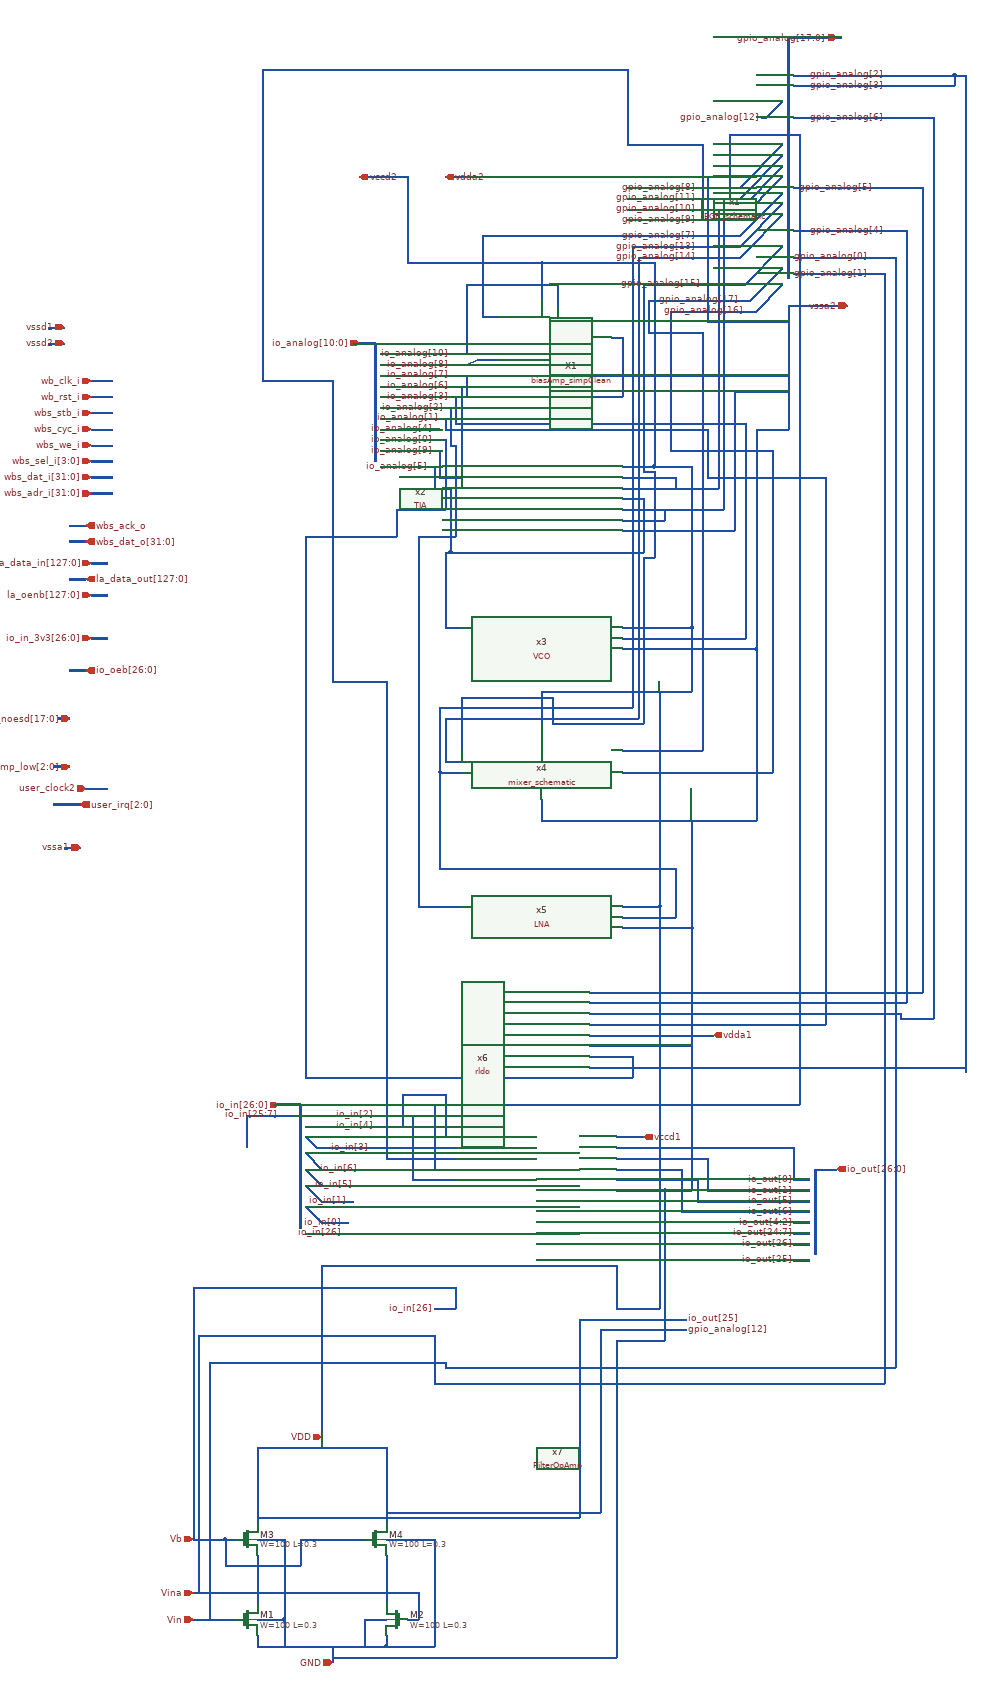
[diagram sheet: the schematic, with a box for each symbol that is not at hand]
v {xschem version=3.0.0 file_version=1.2 }
G {}
K {}
V {}
S {}
E {}
N 5340 -670 5340 -550 { lab=gpio_analog[17:0]
bus=true}
N 5340 -550 5340 -530 { lab=gpio_analog[17:0]
bus=true}
N 5040 -550 5250 -550 { lab=gpio_analog[8]}
N 5250 -550 5330 -630 { lab=gpio_analog[8]}
N 5040 -530 5250 -530 { lab=gpio_analog[11]}
N 5250 -530 5330 -610 { lab=gpio_analog[11]}
N 5040 -510 5250 -510 { lab=gpio_analog[10]}
N 5250 -510 5330 -590 { lab=gpio_analog[10]}
N 5040 -490 5250 -490 { lab=gpio_analog[9]}
N 5250 -490 5330 -570 { lab=gpio_analog[9]}
N 5340 -330 5450 -330 { lab=vssa2}
N 5340 -330 5340 -100 { lab=vssa2}
N 5040 -570 5190 -570 { lab=vssa2}
N 5190 -570 5190 -300 { lab=vssa2}
N 5190 -300 5330 -300 { lab=vssa2}
N 5330 -300 5340 -300 { lab=vssa2}
N 4880 -410 4880 -340 { lab=vccd2}
N 4630 -410 4880 -410 { lab=vccd2}
N 4630 -570 4630 -410 { lab=vccd2}
N 4880 -200 5340 -200 { lab=vssa2}
N 4530 -260 4570 -260 { lab=io_analog[10:0]
bus=true}
N 4580 -240 4670 -240 { lab=io_analog[10]}
N 4670 -240 4740 -240 { lab=io_analog[10]}
N 4740 -370 4740 -240 { lab=io_analog[10]}
N 4740 -370 4910 -370 { lab=io_analog[10]}
N 4580 -220 4740 -220 { lab=io_analog[8]}
N 4740 -220 4760 -230 { lab=io_analog[8]}
N 4760 -230 4800 -230 { lab=io_analog[8]}
N 4770 -310 4800 -310 { lab=gpio_analog[7]}
N 4770 -430 4770 -310 { lab=gpio_analog[7]}
N 4770 -460 4770 -430 { lab=gpio_analog[7]}
N 4770 -460 5250 -460 { lab=gpio_analog[7]}
N 5250 -460 5330 -540 { lab=gpio_analog[7]}
N 4580 -200 4740 -200 { lab=io_analog[7]}
N 4740 -200 4740 -160 { lab=io_analog[7]}
N 4740 -160 5030 -160 { lab=io_analog[7]}
N 5030 -270 5030 -160 { lab=io_analog[7]}
N 5010 -270 5030 -270 { lab=io_analog[7]}
N 5030 -30 5090 -30 { lab=vccd2}
N 5090 -410 5090 -30 { lab=vccd2}
N 4880 -410 5090 -410 { lab=vccd2}
N 5030 90 5240 90 { lab=vssa2}
N 5240 -170 5240 90 { lab=vssa2}
N 5240 -170 5340 -170 { lab=vssa2}
N 5030 10 5210 10 { lab=gpio_analog[10]}
N 5210 -510 5210 10 { lab=gpio_analog[10]}
N 5030 -10 5130 -10 { lab=gpio_analog[10]}
N 5130 -10 5130 10 { lab=gpio_analog[10]}
N 5030 50 5220 50 { lab=gpio_analog[11]}
N 5220 -530 5220 50 { lab=gpio_analog[11]}
N 4580 -180 4730 -180 { lab=io_analog[6]}
N 4730 -180 4730 -30 { lab=io_analog[6]}
N 5030 70 5110 70 { lab=gpio_analog[11]}
N 5110 50 5110 70 { lab=gpio_analog[11]}
N 4710 10 4710 130 { lab=io_analog[5]}
N 4710 130 5070 130 { lab=io_analog[5]}
N 5070 30 5070 130 { lab=io_analog[5]}
N 5030 30 5070 30 { lab=io_analog[5]}
N 4700 270 4730 270 { lab=io_analog[5]}
N 4700 130 4700 270 { lab=io_analog[5]}
N 4700 130 4710 130 { lab=io_analog[5]}
N 5030 310 5280 310 { lab=vssa2}
N 5280 -100 5280 310 { lab=vssa2}
N 5280 -100 5340 -100 { lab=vssa2}
N 5030 270 5080 270 { lab=vccd2}
N 5160 -30 5160 190 { lab=vccd2}
N 5090 -30 5160 -30 { lab=vccd2}
N 5080 270 5160 270 { lab=vccd2}
N 5160 190 5160 270 { lab=vccd2}
N 4580 -160 4720 -160 { lab=io_analog[3]}
N 4720 -160 4720 -110 { lab=io_analog[3]}
N 4720 -110 5260 -110 { lab=io_analog[3]}
N 5260 -110 5260 290 { lab=io_analog[3]}
N 5030 290 5260 290 { lab=io_analog[3]}
N 4880 390 4880 450 { lab=vccd2}
N 4880 390 5160 390 { lab=vccd2}
N 5160 270 5160 390 { lab=vccd2}
N 4880 590 4880 630 { lab=vssa2}
N 4880 630 5280 630 { lab=vssa2}
N 5280 310 5280 630 { lab=vssa2}
N 4690 420 4690 540 { lab=gpio_analog[13]}
N 4690 540 4730 540 { lab=gpio_analog[13]}
N 5250 -440 5330 -520 { lab=gpio_analog[13]}
N 5050 -440 5250 -440 { lab=gpio_analog[13]}
N 5050 -440 5050 420 { lab=gpio_analog[13]}
N 4690 420 5050 420 { lab=gpio_analog[13]}
N 5340 -530 5340 -450 { lab=gpio_analog[17:0]
bus=true}
N 5260 -430 5330 -500 { lab=gpio_analog[14]}
N 5250 -420 5260 -430 { lab=gpio_analog[14]}
N 5060 -420 5250 -420 { lab=gpio_analog[14]}
N 5060 -420 5060 440 { lab=gpio_analog[14]}
N 4700 440 5060 440 { lab=gpio_analog[14]}
N 4700 440 4700 520 { lab=gpio_analog[14]}
N 4700 520 4730 520 { lab=gpio_analog[14]}
N 5260 -370 5330 -440 { lab=gpio_analog[15]}
N 5070 -370 5260 -370 { lab=gpio_analog[15]}
N 4900 450 5070 450 { lab=gpio_analog[15]}
N 4900 400 4900 450 { lab=gpio_analog[15]}
N 4730 400 4900 400 { lab=gpio_analog[15]}
N 4730 400 4730 500 { lab=gpio_analog[15]}
N 5340 -450 5340 -410 { lab=gpio_analog[17:0]
bus=true}
N 5270 -340 5330 -400 { lab=gpio_analog[17]}
N 5080 -340 5270 -340 { lab=gpio_analog[17]}
N 5030 500 5080 500 { lab=gpio_analog[17]}
N 5080 -340 5080 -280 { lab=gpio_analog[17]}
N 5080 -280 5180 -280 { lab=gpio_analog[17]}
N 5180 -280 5180 500 { lab=gpio_analog[17]}
N 5080 500 5180 500 { lab=gpio_analog[17]}
N 5340 -410 5340 -380 { lab=gpio_analog[17:0]
bus=true}
N 5280 -320 5330 -370 { lab=gpio_analog[16]}
N 5120 -320 5280 -320 { lab=gpio_analog[16]}
N 5120 -320 5120 -60 { lab=gpio_analog[16]}
N 5120 -60 5310 -60 { lab=gpio_analog[16]}
N 5310 -60 5310 540 { lab=gpio_analog[16]}
N 5030 540 5310 540 { lab=gpio_analog[16]}
N 5030 790 5100 790 { lab=vccd2}
N 5100 390 5100 790 { lab=vccd2}
N 5030 830 5160 830 { lab=vssa2}
N 5160 630 5160 830 { lab=vssa2}
N 4650 790 4730 790 { lab=io_analog[2]}
N 4650 400 4650 790 { lab=io_analog[2]}
N 4690 540 4690 720 { lab=gpio_analog[13]}
N 4690 720 5130 720 { lab=gpio_analog[13]}
N 5130 720 5130 810 { lab=gpio_analog[13]}
N 5030 810 5130 810 { lab=gpio_analog[13]}
N 5020 1220 5070 1220 { lab=vccd1}
N 5160 830 5160 1320 { lab=vssa2}
N 4680 1280 4720 1280 { lab=gpio_analog[8]}
N 4680 1210 4680 1280 { lab=gpio_analog[8]}
N 4680 1160 4680 1210 { lab=gpio_analog[8]}
N 4680 1160 5220 1160 { lab=gpio_analog[8]}
N 5220 1160 5360 1160 { lab=gpio_analog[8]}
N 5360 -650 5360 1160 { lab=gpio_analog[8]}
N 5230 -650 5360 -650 { lab=gpio_analog[8]}
N 5230 -650 5230 -550 { lab=gpio_analog[8]}
N 4580 -140 4710 -140 { lab=io_analog[2]}
N 4710 -140 4710 -70 { lab=io_analog[2]}
N 4710 -70 4720 -70 { lab=io_analog[2]}
N 4720 -70 4720 100 { lab=io_analog[2]}
N 4660 100 4720 100 { lab=io_analog[2]}
N 4650 100 4660 100 { lab=io_analog[2]}
N 4650 100 4650 400 { lab=io_analog[2]}
N 4640 1300 4720 1300 { lab=io_in[2]}
N 4380 1160 4430 1160 { lab=io_in[26:0]
bus=true}
N 4430 1160 4430 1210 { lab=io_in[26:0]
bus=true}
N 4440 1180 4640 1180 { lab=io_in[2]}
N 4640 1180 4640 1300 { lab=io_in[2]}
N 4700 1220 4720 1220 { lab=io_in[4]}
N 4700 1140 4700 1220 { lab=io_in[4]}
N 4440 1200 4620 1200 { lab=io_in[4]}
N 4620 1140 4620 1200 { lab=io_in[4]}
N 4620 1140 4700 1140 { lab=io_in[4]}
N 4610 1260 4720 1260 { lab=gpio_analog[9]}
N 5340 -830 5340 -670 { lab=gpio_analog[17:0]
bus=true}
N 5340 -830 5440 -830 { lab=gpio_analog[17:0]
bus=true}
N 4590 1260 4610 1260 { lab=gpio_analog[9]}
N 4590 370 4590 1260 { lab=gpio_analog[9]}
N 4490 370 4590 370 { lab=gpio_analog[9]}
N 4490 -190 4490 370 { lab=gpio_analog[9]}
N 4360 -190 4490 -190 { lab=gpio_analog[9]}
N 4360 -760 4360 -190 { lab=gpio_analog[9]}
N 4360 -770 4360 -760 { lab=gpio_analog[9]}
N 4360 -770 5040 -770 { lab=gpio_analog[9]}
N 4500 1240 4720 1240 { lab=io_in[3]}
N 4440 1220 4460 1240 { lab=io_in[3]}
N 4460 1240 4500 1240 { lab=io_in[3]}
N 5020 1280 5080 1280 { lab=io_out[6]}
N 4430 1210 4430 1250 { lab=io_in[26:0]
bus=true}
N 4440 1250 4470 1280 { lab=io_in[6]}
N 4470 1280 4550 1280 { lab=io_in[6]}
N 5020 1300 5110 1300 { lab=io_out[5]}
N 4430 1250 4430 1270 { lab=io_in[26:0]
bus=true}
N 4440 1280 4470 1310 { lab=io_in[5]}
N 4470 1310 4530 1310 { lab=io_in[5]}
N 4530 1310 4540 1310 { lab=io_in[5]}
N 5020 1260 5190 1260 { lab=io_out[1]}
N 4430 1270 4430 1340 { lab=io_in[26:0]
bus=true}
N 4440 1310 4470 1340 { lab=io_in[1]}
N 4470 1340 4530 1340 { lab=io_in[1]}
N 4440 1350 4470 1380 { lab=io_in[0]}
N 4470 1380 4520 1380 { lab=io_in[0]}
N 5020 1240 5140 1240 { lab=io_out[0]}
N 4580 -120 4700 -120 { lab=io_analog[1]}
N 4700 -120 4700 -100 { lab=io_analog[1]}
N 4700 -100 5190 -100 { lab=io_analog[1]}
N 5190 -100 5190 -10 { lab=io_analog[1]}
N 5190 -10 5410 -10 { lab=io_analog[1]}
N 5030 1010 5410 1010 { lab=io_analog[1]}
N 5410 -10 5410 1010 { lab=io_analog[1]}
N 4440 1110 5050 1110 { lab=io_analog[0]}
N 4440 100 4440 1110 { lab=io_analog[0]}
N 4440 100 4610 100 { lab=io_analog[0]}
N 4610 50 4610 100 { lab=io_analog[0]}
N 4610 50 4700 50 { lab=io_analog[0]}
N 4700 -80 4700 50 { lab=io_analog[0]}
N 4590 -80 4700 -80 { lab=io_analog[0]}
N 4580 -80 4590 -80 { lab=io_analog[0]}
N 5350 -470 5400 -470 { lab=gpio_analog[4]}
N 5400 -470 5560 -470 { lab=gpio_analog[4]}
N 5560 -470 5560 960 { lab=gpio_analog[4]}
N 5030 970 5560 970 { lab=gpio_analog[4]}
N 5560 960 5560 970 { lab=gpio_analog[4]}
N 5350 -550 5590 -550 { lab=gpio_analog[5]}
N 5590 -550 5590 950 { lab=gpio_analog[5]}
N 5030 950 5590 950 { lab=gpio_analog[5]}
N 5350 -680 5610 -680 { lab=gpio_analog[6]}
N 5610 -680 5610 1000 { lab=gpio_analog[6]}
N 5030 990 5550 990 { lab=gpio_analog[6]}
N 5550 990 5550 1000 { lab=gpio_analog[6]}
N 5550 1000 5610 1000 { lab=gpio_analog[6]}
N 5350 -740 5650 -740 { lab=gpio_analog[3]}
N 5040 -770 5040 -630 { lab=gpio_analog[9]}
N 5040 -630 5180 -630 { lab=gpio_analog[9]}
N 5180 -630 5180 -490 { lab=gpio_analog[9]}
N 4540 -570 4630 -570 { lab=vccd2}
N 4700 -570 4740 -570 { lab=vdda2}
N 5300 -680 5330 -710 { lab=gpio_analog[12]}
N 5290 -680 5300 -680 { lab=gpio_analog[12]}
N 4570 -260 4570 -90 { lab=io_analog[10:0]
bus=true}
N 4570 -90 4570 -70 { lab=io_analog[10:0]
bus=true}
N 4580 -60 4690 -60 { lab=io_analog[9]}
N 4690 -60 4690 -10 { lab=io_analog[9]}
N 4690 -10 4730 -10 { lab=io_analog[9]}
N 4570 -70 4570 -40 { lab=io_analog[10:0]
bus=true}
N 4580 -30 4680 -30 { lab=io_analog[5]}
N 4680 -30 4680 10 { lab=io_analog[5]}
N 4680 10 4710 10 { lab=io_analog[5]}
N 4580 -100 4690 -100 { lab=io_analog[4]}
N 5350 -390 5520 -390 { lab=gpio_analog[1]}
N 5350 -420 5540 -420 { lab=gpio_analog[0]}
N 5540 -420 5540 1020 { lab=gpio_analog[0]}
N 4390 1180 4420 1180 { lab=io_in[25:7]}
N 4330 1180 4390 1180 { lab=io_in[25:7]}
N 4330 1180 4330 1240 { lab=io_in[25:7]}
N 3960 -290 3990 -290 { lab=vssd1}
N 3960 -260 3990 -260 { lab=vssd2}
N 4040 -190 4080 -190 { lab=wb_clk_i}
N 4040 -160 4080 -160 { lab=wb_rst_i}
N 4040 -130 4080 -130 { lab=wbs_stb_i}
N 4040 -100 4080 -100 { lab=wbs_cyc_i}
N 4040 -70 4080 -70 { lab=wbs_we_i}
N 4040 -40 4080 -40 { lab=wbs_sel_i[3:0]
bus=true}
N 4040 -10 4080 -10 { lab=wbs_dat_i[31:0]
bus=true}
N 4040 20 4080 20 { lab=wbs_adr_i[31:0]
bus=true}
N 4000 80 4030 80 { lab=wbs_ack_o}
N 4000 110 4030 110 { lab=wbs_dat_o[31:0]
bus=true}
N 4040 150 4070 150 { lab=la_data_in[127:0]
bus=true
}
N 4000 180 4030 180 { lab=la_data_out[127:0]
bus=true}
N 4040 210 4070 210 { lab=la_oenb[127:0]
bus=true
}
N 4040 290 4070 290 { lab=io_in_3v3[26:0]
bus=true}
N 4000 350 4030 350 { lab=io_oeb[26:0]
bus=true}
N 3980 440 4000 440 { lab=gpio_noesd[17:0]
bus=true}
N 3970 530 4000 530 { lab=io_clamp_low[2:0]
bus=true}
N 4030 570 4070 570 { lab=user_clock2}
N 3970 600 4020 600 { lab=user_irq[2:0]
bus=true}
N 5070 140 5070 450 { lab=gpio_analog[15]}
N 5070 140 5090 140 { lab=gpio_analog[15]}
N 5090 -20 5090 140 { lab=gpio_analog[15]}
N 5070 -20 5090 -20 { lab=gpio_analog[15]}
N 5070 -370 5070 -20 { lab=gpio_analog[15]}
N 5390 1280 5430 1280 { lab=io_out[26:0]}
N 5390 1280 5390 1390 { lab=io_out[26:0]
bus=true}
N 5350 1300 5380 1300 { lab=io_out[0]}
N 5350 1320 5380 1320 { lab=io_out[1]}
N 5350 1340 5380 1340 { lab=io_out[5]}
N 5350 1360 5380 1360 { lab=io_out[6]}
N 5350 1380 5380 1380 { lab=io_out[4:2]}
N 5140 1240 5350 1240 { lab=io_out[0]}
N 5350 1240 5350 1300 { lab=io_out[0]}
N 5190 1260 5190 1310 { lab=io_out[1]}
N 5190 1310 5190 1320 { lab=io_out[1]}
N 5190 1320 5350 1320 { lab=io_out[1]}
N 5080 1280 5140 1280 { lab=io_out[6]}
N 5140 1280 5140 1360 { lab=io_out[6]}
N 5140 1360 5350 1360 { lab=io_out[6]}
N 5110 1300 5170 1300 { lab=io_out[5]}
N 5170 1300 5170 1340 { lab=io_out[5]}
N 5170 1340 5350 1340 { lab=io_out[5]}
N 5350 1400 5380 1400 { lab=io_out[24:7]}
N 4910 -370 4910 -327.5 { lab=io_analog[10]}
N 5020 1540 5070 1540 { lab=vccd2}
N 5110 1320 5110 1600 { lab=vssa2}
N 5020 1600 5110 1600 { lab=vssa2}
N 4680 1540 4720 1540 { lab=io_in[26]}
N 5520 -390 5520 1610 { lab=gpio_analog[1]}
N 4680 1650 4680 1680 { lab=gpio_analog[1]}
N 4700 1650 5540 1650 { lab=gpio_analog[0]}
N 5540 1600 5540 1650 { lab=gpio_analog[0]}
N 5520 1610 5520 1680 { lab=gpio_analog[1]}
N 4680 1680 5520 1680 { lab=gpio_analog[1]}
N 5020 1560 5150 1560 { lab=io_out[25]}
N 4430 1340 4430 1390 { lab=io_in[26:0]
bus = true}
N 4440 1400 4520 1400 { lab=io_in[26]}
N 5350 1420 5380 1420 { lab=io_out[26]}
N 5390 1390 5390 1410 { lab=io_out[26:0]
bus=true}
N 5350 1450 5380 1450 { lab=io_out[25]}
N 5390 1410 5390 1440 { lab=io_out[26:0]
bus=true}
N 5540 1020 5540 1610 { lab=gpio_analog[0]}
N 5100 790 5100 1540 { lab=vccd2}
N 5070 1540 5100 1540 { lab=vccd2}
N 5110 1320 5160 1320 { lab=vssa2}
N 5020 1580 5150 1580 { lab=gpio_analog[12]}
N 5650 -760 5670 -760 { lab=gpio_analog[2]}
N 5350 -760 5650 -760 { lab=gpio_analog[2]}
N 3990 680 4020 680 { lab=vssa1}
N 5020 1320 5110 1320 { lab=vssa2}
N 4350 2000 4350 2090 { lab=#net1}
N 4590 2000 4590 2090 { lab=#net2}
N 4350 2150 4350 2170 { lab=vssa2}
N 4350 2170 4590 2170 { lab=vssa2}
N 4590 2150 4590 2170 { lab=vssa2}
N 4350 2120 4400 2120 { lab=vssa2}
N 4400 2120 4400 2170 { lab=vssa2}
N 4350 1970 4400 1970 { lab=vssa2}
N 4400 1970 4400 2120 { lab=vssa2}
N 4430 1970 4550 1970 { lab=io_in[26]}
N 4430 1970 4430 2020 { lab=io_in[26]}
N 4290 2020 4430 2020 { lab=io_in[26]}
N 4290 1970 4290 2020 { lab=io_in[26]}
N 4290 1970 4310 1970 { lab=io_in[26]}
N 4230 1970 4290 1970 { lab=Vb}
N 4550 2120 4590 2120 { lab=vssa2}
N 4550 2120 4550 2170 { lab=vssa2}
N 4630 2120 4650 2120 { lab=gpio_analog[1]}
N 4650 2070 4650 2120 { lab=gpio_analog[1]}
N 4230 2120 4310 2120 { lab=Vin}
N 4230 2070 4650 2070 { lab=Vina}
N 4350 1880 4350 1940 { lab=gpio_analog[12]}
N 4590 1880 4590 1940 { lab=gpio_analog[12]}
N 4590 1970 4680 1970 { lab=vssa2}
N 4680 1970 4680 2170 { lab=vssa2}
N 4590 2170 4680 2170 { lab=vssa2}
N 4350 1800 4350 1820 { lab=gpio_analog[12]}
N 4350 1800 4590 1800 { lab=gpio_analog[12]}
N 4590 1800 4590 1820 { lab=gpio_analog[12]}
N 4470 1780 4470 1800 { lab=VDD}
N 4490 2170 4490 2200 { lab=GND}
N 4590 1820 4590 1880 { lab=gpio_analog[12]}
N 4350 1820 4350 1880 { lab=gpio_analog[12]}
N 5020 1460 5020 1540 { lab=vccd2}
N 4470 1460 5020 1460 { lab=vccd2}
N 4470 1460 4470 1770 { lab=vccd2}
N 4230 1500 4230 1970 { lab=Vb}
N 4230 1500 4720 1500 { lab=io_in[26]}
N 4240 1590 4240 2070 { lab=gpio_analog[1]}
N 4240 1590 4680 1590 { lab=gpio_analog[1]}
N 4260 1640 4260 2120 { lab=gpio_analog[0]}
N 4260 1640 4700 1640 { lab=gpio_analog[0]}
N 4700 1640 4700 1650 { lab=gpio_analog[0]}
N 4680 1590 4680 1650 { lab=gpio_analog[1]}
N 4720 1500 4720 1540 { lab=io_in[26]}
N 5020 1600 5020 2190 { lab=vssa2}
N 4490 2190 5020 2190 { lab=vssa2}
N 4990 1580 5020 1580 { lab=gpio_analog[12]}
N 4990 1580 4990 1870 { lab=gpio_analog[12]}
N 4350 1930 4950 1930 { lab=gpio_analog[12]}
N 4950 1560 4950 1930 { lab=gpio_analog[12]}
N 4590 1920 4990 1920 { lab=gpio_analog[12]}
N 4990 1870 4990 1920 { lab=gpio_analog[12]}
N 4950 1560 5020 1560 { lab=gpio_analog[12]}
N 4970 1010 5030 1010 { lab=io_analog[1]}
N 4970 1070 5050 1070 { lab=io_analog[0]}
N 5050 1070 5050 1110 { lab=io_analog[0]}
N 4970 990 5030 990 { lab=gpio_analog[6]}
N 4970 1030 5200 1030 { lab=vdda1}
N 4970 950 5030 950 { lab=gpio_analog[5]}
N 4970 970 5030 970 { lab=gpio_analog[4]}
N 4970 1050 5160 1050 { lab=vssa2}
N 5650 -760 5650 -740 { lab=gpio_analog[2]}
N 5670 -760 5670 1100 { lab=gpio_analog[2]}
N 4970 1090 5220 1090 { lab=gpio_analog[2]}
N 5220 1090 5670 1090 { lab=gpio_analog[2]}
C {iopin.sym} 4020 680 0 0 {name=p3 lab=vssa1}
C {iopin.sym} 5070 1220 2 1 {name=p5 lab=vccd1}
C {ipin.sym} 4390 1160 0 0 {name=p21 lab=io_in[26:0]}
C {iopin.sym} 5430 -830 0 0 {name=p26 lab=gpio_analog[17:0]}
C {iopin.sym} 4540 -260 2 0 {name=p29 lab=io_analog[10:0]}
C {/research/mlab/chipathon/Final_schematic/BGR_schematic.sym} 4890 -530 0 0 {name=x1}
C {bus_connect_nolab.sym} 5340 -640 2 0 {name=r1}
C {bus_connect_nolab.sym} 5340 -620 2 0 {name=r2}
C {bus_connect_nolab.sym} 5340 -600 2 0 {name=r3}
C {bus_connect_nolab.sym} 5340 -580 2 0 {name=r4}
C {bus_connect_nolab.sym} 5340 -550 2 0 {name=r5}
C {bus_connect_nolab.sym} 5340 -530 2 0 {name=r6}
C {lab_wire.sym} 5170 -550 0 0 {name=l33 sig_type=std_logic lab=gpio_analog[8]}
C {lab_wire.sym} 5170 -530 0 0 {name=l34 sig_type=std_logic lab=gpio_analog[11]}
C {lab_wire.sym} 5170 -510 0 0 {name=l35 sig_type=std_logic lab=gpio_analog[10]}
C {lab_wire.sym} 5170 -490 0 0 {name=l36 sig_type=std_logic lab=gpio_analog[9]}
C {/research/mlab/chipathon/Final_schematic/biasAmp_simpClean.sym} 4880 -270 0 0 {name=X1}
C {bus_connect_nolab.sym} 4570 -250 1 0 {name=r13
}
C {lab_wire.sym} 4710 -240 0 0 {name=l37 sig_type=std_logic lab=io_analog[10]}
C {bus_connect_nolab.sym} 4570 -230 1 0 {name=r14
}
C {lab_wire.sym} 4710 -220 0 0 {name=l38 sig_type=std_logic lab=io_analog[8]}
C {lab_wire.sym} 5170 -460 0 0 {name=l39 sig_type=std_logic lab=gpio_analog[7]}
C {bus_connect_nolab.sym} 4570 -210 1 0 {name=r15
}
C {lab_wire.sym} 4710 -200 0 0 {name=l40 sig_type=std_logic lab=io_analog[7]}
C {bus_connect_nolab.sym} 4570 -190 1 0 {name=r16
}
C {lab_wire.sym} 4710 -180 0 0 {name=l42 sig_type=std_logic lab=io_analog[6]}
C {bus_connect_nolab.sym} 4570 -40 1 0 {name=r17
}
C {/research/mlab/chipathon/Final_schematic/VCO.sym} 4880 290 0 0 {name=x3}
C {bus_connect_nolab.sym} 4570 -170 1 0 {name=r18
}
C {lab_wire.sym} 4710 -160 0 0 {name=l44 sig_type=std_logic lab=io_analog[3]}
C {/research/mlab/chipathon/Final_schematic/mixer_schematic.sym} 4880 520 0 0 {name=x4}
C {lab_wire.sym} 5170 -440 0 0 {name=l45 sig_type=std_logic lab=gpio_analog[13]}
C {bus_connect_nolab.sym} 5340 -510 2 0 {name=r8}
C {lab_wire.sym} 5170 -420 0 0 {name=l46 sig_type=std_logic lab=gpio_analog[14]}
C {bus_connect_nolab.sym} 5340 -450 2 0 {name=r9}
C {lab_wire.sym} 5180 -370 0 0 {name=l47 sig_type=std_logic lab=gpio_analog[15]}
C {bus_connect_nolab.sym} 5340 -410 2 0 {name=r10}
C {lab_wire.sym} 5250 -340 0 0 {name=l48 sig_type=std_logic lab=gpio_analog[17]}
C {bus_connect_nolab.sym} 5340 -380 2 0 {name=r11}
C {lab_wire.sym} 5260 -320 0 0 {name=l49 sig_type=std_logic lab=gpio_analog[16]}
C {/research/mlab/chipathon/Final_schematic/LNA.sym} 4880 810 0 0 {name=x5}
C {/research/mlab/chipathon/Final_schematic/FilterOpAmp.sym} 4870 1270 0 0 {name=x7}
C {bus_connect_nolab.sym} 4570 -150 1 0 {name=r27
}
C {lab_wire.sym} 4700 -140 0 0 {name=l50 sig_type=std_logic lab=io_analog[2]}
C {bus_connect_nolab.sym} 4430 1170 1 0 {name=r19}
C {lab_wire.sym} 4570 1180 0 0 {name=l51 sig_type=std_logic lab=io_in[2]}
C {bus_connect_nolab.sym} 4430 1190 1 0 {name=r20}
C {lab_wire.sym} 4570 1200 0 0 {name=l52 sig_type=std_logic lab=io_in[4]}
C {bus_connect_nolab.sym} 4430 1210 1 0 {name=r22}
C {lab_wire.sym} 4560 1240 0 0 {name=l54 sig_type=std_logic lab=io_in[3]}
C {bus_connect_nolab.sym} 4430 1240 1 0 {name=r23}
C {lab_wire.sym} 4540 1280 0 0 {name=l55 sig_type=std_logic lab=io_in[6]}
C {bus_connect_nolab.sym} 4430 1270 1 0 {name=r24}
C {lab_wire.sym} 4530 1310 0 0 {name=l56 sig_type=std_logic lab=io_in[5]}
C {bus_connect_nolab.sym} 4430 1300 1 0 {name=r25}
C {lab_wire.sym} 4520 1340 0 0 {name=l57 sig_type=std_logic lab=io_in[1]}
C {bus_connect_nolab.sym} 4430 1340 1 0 {name=r26}
C {lab_wire.sym} 4510 1380 0 0 {name=l58 sig_type=std_logic lab=io_in[0]}
C {bus_connect_nolab.sym} 4570 -130 1 0 {name=r28
}
C {lab_wire.sym} 4690 -120 0 0 {name=l59 sig_type=std_logic lab=io_analog[1]}
C {bus_connect_nolab.sym} 4570 -90 1 0 {name=r34
}
C {lab_wire.sym} 4680 -80 0 0 {name=l60 sig_type=std_logic lab=io_analog[0]}
C {bus_connect_nolab.sym} 5340 -480 1 0 {name=r29}
C {lab_wire.sym} 5520 -470 0 0 {name=l61 sig_type=std_logic lab=gpio_analog[4]}
C {bus_connect_nolab.sym} 5340 -560 1 0 {name=r30}
C {lab_wire.sym} 5500 -550 0 0 {name=l62 sig_type=std_logic lab=gpio_analog[5]}
C {bus_connect_nolab.sym} 5340 -690 1 0 {name=r31}
C {lab_wire.sym} 5520 -680 0 0 {name=l63 sig_type=std_logic lab=gpio_analog[6]}
C {bus_connect_nolab.sym} 5340 -770 1 0 {name=r32}
C {bus_connect_nolab.sym} 5340 -750 1 0 {name=r33}
C {lab_wire.sym} 5490 -420 0 0 {name=l64 sig_type=std_logic lab=gpio_analog[0]}
C {lab_wire.sym} 5490 -390 0 0 {name=l65 sig_type=std_logic lab=gpio_analog[1]}
C {bus_connect_nolab.sym} 5340 -720 2 0 {name=r21}
C {lab_wire.sym} 5150 1580 0 1 {name=l53 sig_type=std_logic lab=gpio_analog[12]}
C {bus_connect_nolab.sym} 4570 -70 1 0 {name=r35
}
C {lab_wire.sym} 4680 -60 0 0 {name=l41 sig_type=std_logic lab=io_analog[9]}
C {lab_wire.sym} 4670 -30 0 0 {name=l43 sig_type=std_logic lab=io_analog[5]}
C {bus_connect_nolab.sym} 4570 -110 1 0 {name=r36
}
C {lab_wire.sym} 4680 -100 0 0 {name=l66 sig_type=std_logic lab=io_analog[4]}
C {bus_connect_nolab.sym} 5340 -430 1 0 {name=r7}
C {bus_connect_nolab.sym} 5340 -400 1 0 {name=r12}
C {lab_wire.sym} 5520 -760 0 0 {name=l67 sig_type=std_logic lab=gpio_analog[2]}
C {lab_wire.sym} 5520 -740 0 0 {name=l68 sig_type=std_logic lab=gpio_analog[3]}
C {bus_connect_nolab.sym} 4430 1170 2 0 {name=r37}
C {lab_wire.sym} 4390 1180 3 0 {name=l1 sig_type=std_logic lab=io_in[25:7]}
C {noconn.sym} 4330 1240 0 0 {name=l2}
C {iopin.sym} 5450 -330 0 0 {name=p4 lab=vssa2}
C {iopin.sym} 4540 -570 0 1 {name=p6 lab=vccd2}
C {iopin.sym} 3990 -290 0 0 {name=p7 lab=vssd1}
C {iopin.sym} 3990 -260 0 0 {name=p8 lab=vssd2}
C {ipin.sym} 4040 -190 0 0 {name=p9 lab=wb_clk_i}
C {ipin.sym} 4040 -160 0 0 {name=p10 lab=wb_rst_i}
C {ipin.sym} 4040 -130 0 0 {name=p11 lab=wbs_stb_i}
C {ipin.sym} 4040 -100 0 0 {name=p12 lab=wbs_cyc_i}
C {ipin.sym} 4040 -70 0 0 {name=p13 lab=wbs_we_i}
C {ipin.sym} 4040 -40 0 0 {name=p14 lab=wbs_sel_i[3:0]}
C {ipin.sym} 4040 -10 0 0 {name=p15 lab=wbs_dat_i[31:0]}
C {ipin.sym} 4040 20 0 0 {name=p16 lab=wbs_adr_i[31:0]}
C {opin.sym} 4030 80 0 0 {name=p17 lab=wbs_ack_o}
C {opin.sym} 4030 110 0 0 {name=p18 lab=wbs_dat_o[31:0]}
C {ipin.sym} 4040 150 0 0 {name=p19 lab=la_data_in[127:0]}
C {opin.sym} 4030 180 0 0 {name=p20 lab=la_data_out[127:0]}
C {ipin.sym} 4040 290 0 0 {name=p22 lab=io_in_3v3[26:0]}
C {ipin.sym} 4030 570 0 0 {name=p23 lab=user_clock2}
C {opin.sym} 4030 350 0 0 {name=p25 lab=io_oeb[26:0]}
C {iopin.sym} 4000 440 0 0 {name=p27 lab=gpio_noesd[17:0]}
C {iopin.sym} 4000 530 0 0 {name=p31 lab=io_clamp_low[2:0]}
C {opin.sym} 4020 600 0 0 {name=p32 lab=user_irq[2:0]}
C {ipin.sym} 4040 210 0 0 {name=p28 lab=la_oenb[127:0]}
C {noconn.sym} 3960 -290 0 0 {name=l75}
C {noconn.sym} 3960 -260 0 0 {name=l76}
C {noconn.sym} 4080 -190 0 1 {name=l3}
C {noconn.sym} 4080 -160 0 1 {name=l4}
C {noconn.sym} 4080 -130 0 1 {name=l5}
C {noconn.sym} 4080 -100 0 1 {name=l6}
C {noconn.sym} 4080 -70 0 1 {name=l7}
C {noconn.sym} 4080 -40 0 1 {name=l8}
C {noconn.sym} 4080 -10 0 1 {name=l9}
C {noconn.sym} 4080 20 0 1 {name=l10}
C {noconn.sym} 4000 80 0 0 {name=l11}
C {noconn.sym} 4000 110 0 0 {name=l12}
C {noconn.sym} 4070 150 0 1 {name=l13}
C {noconn.sym} 4000 180 0 0 {name=l14}
C {noconn.sym} 4070 210 0 1 {name=l77}
C {noconn.sym} 4070 290 0 1 {name=l78}
C {noconn.sym} 4000 350 0 0 {name=l80}
C {noconn.sym} 3980 440 0 0 {name=l81}
C {noconn.sym} 3970 530 0 0 {name=l82}
C {noconn.sym} 3970 600 0 0 {name=l83}
C {noconn.sym} 4070 570 0 1 {name=l84}
C {opin.sym} 5430 1280 0 0 {name=p30 lab=io_out[26:0]}
C {bus_connect_nolab.sym} 5390 1290 2 0 {name=r38}
C {bus_connect_nolab.sym} 5390 1310 2 0 {name=r39}
C {bus_connect_nolab.sym} 5390 1330 2 0 {name=r40}
C {bus_connect_nolab.sym} 5390 1350 2 0 {name=r41}
C {bus_connect_nolab.sym} 5390 1370 2 0 {name=r42}
C {noconn.sym} 4550 1280 0 1 {name=l15}
C {noconn.sym} 4540 1310 0 1 {name=l16}
C {noconn.sym} 4530 1340 0 1 {name=l17}
C {noconn.sym} 4520 1380 0 1 {name=l18}
C {lab_wire.sym} 5350 1300 0 0 {name=l19 sig_type=std_logic lab=io_out[0]}
C {lab_wire.sym} 5350 1320 0 0 {name=l20 sig_type=std_logic lab=io_out[1]}
C {lab_wire.sym} 5350 1340 0 0 {name=l21 sig_type=std_logic lab=io_out[5]}
C {lab_wire.sym} 5350 1360 0 0 {name=l22 sig_type=std_logic lab=io_out[6]}
C {bus_connect_nolab.sym} 5390 1390 2 0 {name=r43}
C {lab_wire.sym} 5350 1380 0 0 {name=l23 sig_type=std_logic lab=io_out[4:2]}
C {lab_wire.sym} 5350 1400 0 0 {name=l24 sig_type=std_logic lab=io_out[24:7]}
C {noconn.sym} 5350 1380 0 0 {name=l25}
C {noconn.sym} 5350 1400 0 0 {name=l26}
C {lab_wire.sym} 4680 1540 0 0 {name=l30 sig_type=std_logic lab=io_in[26]}
C {bus_connect_nolab.sym} 4430 1390 1 0 {name=r44}
C {lab_wire.sym} 4510 1400 0 0 {name=l28 sig_type=std_logic lab=io_in[26]}
C {lab_wire.sym} 5150 1560 0 1 {name=l29 sig_type=std_logic lab=io_out[25]}
C {bus_connect_nolab.sym} 5390 1410 2 0 {name=r45}
C {lab_wire.sym} 5350 1420 0 0 {name=l31 sig_type=std_logic lab=io_out[26]}
C {noconn.sym} 5350 1420 0 0 {name=l32}
C {lab_wire.sym} 5350 1450 0 0 {name=l69 sig_type=std_logic lab=io_out[25]}
C {bus_connect_nolab.sym} 5390 1440 2 0 {name=r46}
C {iopin.sym} 4700 -570 0 1 {name=p24 lab=vdda2}
C {lab_wire.sym} 5290 -680 0 0 {name=l27 sig_type=std_logic lab=gpio_analog[12]}
C {/research/mlab/chipathon/Final_schematic/TIA.sym} 4880 30 0 0 {name=x2}
C {noconn.sym} 3990 680 0 0 {name=l85}
C {sky130_fd_pr/nfet_01v8.sym} 4330 2120 0 0 {name=M1
L=0.3
W=100
nf=1 
mult=6
ad="'int((nf+1)/2) * W/nf * 0.29'" 
pd="'2*int((nf+1)/2) * (W/nf + 0.29)'"
as="'int((nf+2)/2) * W/nf * 0.29'" 
ps="'2*int((nf+2)/2) * (W/nf + 0.29)'"
nrd="'0.29 / W'" nrs="'0.29 / W'"
sa=0 sb=0 sd=0
model=nfet_01v8
spiceprefix=X
}
C {sky130_fd_pr/nfet_01v8.sym} 4610 2120 0 1 {name=M2
L=0.3
W=100
nf=1 
mult=6
ad="'int((nf+1)/2) * W/nf * 0.29'" 
pd="'2*int((nf+1)/2) * (W/nf + 0.29)'"
as="'int((nf+2)/2) * W/nf * 0.29'" 
ps="'2*int((nf+2)/2) * (W/nf + 0.29)'"
nrd="'0.29 / W'" nrs="'0.29 / W'"
sa=0 sb=0 sd=0
model=nfet_01v8
spiceprefix=X
}
C {sky130_fd_pr/nfet_01v8.sym} 4330 1970 0 0 {name=M3
L=0.3
W=100
nf=1 
mult=24
ad="'int((nf+1)/2) * W/nf * 0.29'" 
pd="'2*int((nf+1)/2) * (W/nf + 0.29)'"
as="'int((nf+2)/2) * W/nf * 0.29'" 
ps="'2*int((nf+2)/2) * (W/nf + 0.29)'"
nrd="'0.29 / W'" nrs="'0.29 / W'"
sa=0 sb=0 sd=0
model=nfet_01v8
spiceprefix=X
}
C {sky130_fd_pr/nfet_01v8.sym} 4570 1970 0 0 {name=M4
L=0.3
W=100
nf=1 
mult=24
ad="'int((nf+1)/2) * W/nf * 0.29'" 
pd="'2*int((nf+1)/2) * (W/nf + 0.29)'"
as="'int((nf+2)/2) * W/nf * 0.29'" 
ps="'2*int((nf+2)/2) * (W/nf + 0.29)'"
nrd="'0.29 / W'" nrs="'0.29 / W'"
sa=0 sb=0 sd=0
model=nfet_01v8
spiceprefix=X
}
C {iopin.sym} 4470 1780 3 0 {name=p1 lab=VDD}
C {iopin.sym} 4490 2200 1 0 {name=p2 lab=GND}
C {ipin.sym} 4230 1970 0 0 {name=p33 lab=Vb}
C {ipin.sym} 4230 2070 0 0 {name=p34 lab=Vina}
C {ipin.sym} 4230 2120 0 0 {name=p35 lab=Vin}
C {/research/mlab/chipathon/Final_schematic/rldo.sym} 4820 1020 0 0 {name=x6}
C {iopin.sym} 5200 1030 2 1 {name=p36 lab=vdda1}
